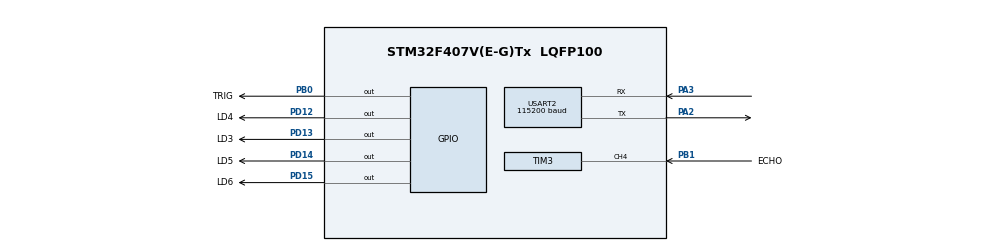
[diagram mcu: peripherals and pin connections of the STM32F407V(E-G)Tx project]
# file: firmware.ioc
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Mcu.Family=STM32F4
Mcu.Name=STM32F407V(E-G)Tx
Mcu.Package=LQFP100
NVIC.PriorityGroup=NVIC_PRIORITYGROUP_4
NVIC.TIM3_IRQn=true\:0\:0\:false\:false\:true\:true\:true\:true
NVIC.USART2_IRQn=true\:0\:0\:false\:false\:true\:true\:true\:true
PA2.Mode=Asynchronous
PA2.Signal=USART2_TX
PA3.Mode=Asynchronous
PA3.Signal=USART2_RX
PB0.GPIO_Label=TRIG
PB0.Signal=GPIO_Output
PB1.GPIO_Label=ECHO
PB1.Signal=S_TIM3_CH4
PD12.GPIO_Label=LD4
PD12.Signal=GPIO_Output
PD13.GPIO_Label=LD3
PD13.Signal=GPIO_Output
PD14.GPIO_Label=LD5
PD14.Signal=GPIO_Output
PD15.GPIO_Label=LD6
PD15.Signal=GPIO_Output
ProjectManager.HeapSize=0x200
ProjectManager.StackSize=0x400
ProjectManager.TargetToolchain=CMake
RCC.48MHZClocksFreq_Value=96000000
RCC.AHBFreq_Value=96000000
RCC.APB1CLKDivider=RCC_HCLK_DIV4
RCC.APB1Freq_Value=24000000
RCC.APB1TimFreq_Value=48000000
RCC.APB2CLKDivider=RCC_HCLK_DIV2
RCC.APB2Freq_Value=48000000
RCC.APB2TimFreq_Value=96000000
RCC.CortexFreq_Value=96000000
RCC.HCLKFreq_Value=96000000
RCC.HSE_VALUE=25000000
RCC.HSI_VALUE=16000000
RCC.LSE_VALUE=32768
RCC.PLLM=8
RCC.PLLN=192
RCC.PLLP=RCC_PLLP_DIV4
RCC.SYSCLKFreq_VALUE=96000000
RCC.SYSCLKSource=RCC_SYSCLKSOURCE_PLLCLK
RCC.VCOOutputFreq_Value=384000000
SH.S_TIM3_CH4.0=TIM3_CH4,Input_Capture4_from_TI4
TIM3.Channel-Input_Capture4_from_TI4=TIM_CHANNEL_4
TIM3.Period=65535
TIM3.Prescaler=48-1
USART2.BaudRate=115200
USART2.VirtualMode=VM_ASYNC
VP_TIM3_VS_ClockSourceINT.Mode=Internal
board=custom

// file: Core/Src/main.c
/* USER CODE BEGIN Header */
/**
  ******************************************************************************
  * @file           : main.c
  * @brief          : Main program body
  ******************************************************************************
  * @attention
  *
  * Copyright (c) 2026 STMicroelectronics.
  * All rights reserved.
  *
  * This software is licensed under terms that can be found in the LICENSE file
  * in the root directory of this software component.
  * If no LICENSE file comes with this software, it is provided AS-IS.
  *
  ******************************************************************************
  */
/* USER CODE END Header */
#include "main.h"
#include "tim.h"
#include "usart.h"
#include "usb_device.h"
#include "gpio.h"

void SystemClock_Config(void);

int main(void)
{

  /* MCU Configuration--------------------------------------------------------*/

  /* Reset of all peripherals, Initializes the Flash interface and the Systick. */
  HAL_Init();

  /* Configure the system clock */
  SystemClock_Config();

  /* Initialize all configured peripherals */
  MX_GPIO_Init();
  MX_TIM3_Init();
  MX_USART2_UART_Init();
  MX_USB_DEVICE_Init();

  /* Infinite loop */
  while (1)
  {

  }
}

void SystemClock_Config(void)
{
  RCC_OscInitTypeDef RCC_OscInitStruct = {0};
  RCC_ClkInitTypeDef RCC_ClkInitStruct = {0};

  /** Configure the main internal regulator output voltage
  */
  __HAL_RCC_PWR_CLK_ENABLE();
  __HAL_PWR_VOLTAGESCALING_CONFIG(PWR_REGULATOR_VOLTAGE_SCALE1);

  /** Initializes the RCC Oscillators according to the specified parameters
  * in the RCC_OscInitTypeDef structure.
  */
  RCC_OscInitStruct.OscillatorType = RCC_OSCILLATORTYPE_HSE;
  RCC_OscInitStruct.HSEState = RCC_HSE_OFF;
  RCC_OscInitStruct.PLL.PLLState = RCC_PLL_ON;
  RCC_OscInitStruct.PLL.PLLSource = RCC_PLLSOURCE_HSE;
  RCC_OscInitStruct.PLL.PLLM = 8;
  RCC_OscInitStruct.PLL.PLLN = 192;
  RCC_OscInitStruct.PLL.PLLP = RCC_PLLP_DIV4;
  RCC_OscInitStruct.PLL.PLLQ = 8;
  if (HAL_RCC_OscConfig(&RCC_OscInitStruct) != HAL_OK)
  {
    Error_Handler();
  }

  /** Initializes the CPU, AHB and APB buses clocks
  */
  RCC_ClkInitStruct.ClockType = RCC_CLOCKTYPE_HCLK|RCC_CLOCKTYPE_SYSCLK
                              |RCC_CLOCKTYPE_PCLK1|RCC_CLOCKTYPE_PCLK2;
  RCC_ClkInitStruct.SYSCLKSource = RCC_SYSCLKSOURCE_PLLCLK;
  RCC_ClkInitStruct.AHBCLKDivider = RCC_SYSCLK_DIV1;
  RCC_ClkInitStruct.APB1CLKDivider = RCC_HCLK_DIV4;
  RCC_ClkInitStruct.APB2CLKDivider = RCC_HCLK_DIV2;

  if (HAL_RCC_ClockConfig(&RCC_ClkInitStruct, FLASH_LATENCY_4) != HAL_OK)
  {
    Error_Handler();
  }
}

void Error_Handler(void)
{
  __disable_irq();
  while (1)
  {
  }
}
